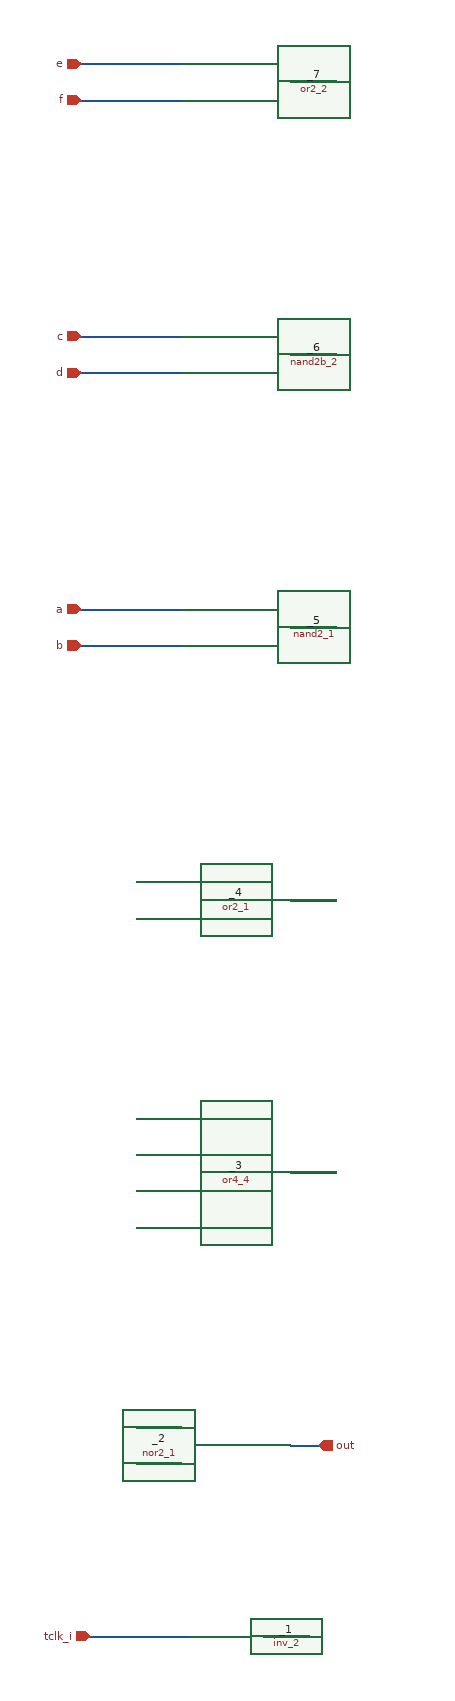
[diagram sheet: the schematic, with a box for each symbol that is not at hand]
v {xschem version=3.4.8RC file_version=1.3}
G {}
K {}
V {}
S {}
F {}
E {}
N 70 2800 180 2800 {lab=tclk_i}
N 60 1670 170 1670 {lab=a}
N 60 1710 170 1710 {lab=b}
N 60 1370 170 1370 {lab=c}
N 60 1410 170 1410 {lab=d}
N 60 1070 170 1070 {lab=e}
N 60 1110 170 1110 {lab=f}
N 290 1090 340 1090 {lab=#net1}
N 120 2310 170 2310 {lab=#net2}
N 120 2010 170 2010 {lab=#net3}
N 290 2290 340 2290 {lab=#net4}
N 120 2570 170 2570 {lab=#net5}
N 290 1690 340 1690 {lab=#net6}
N 120 2230 170 2230 {lab=#net7}
N 290 1990 340 1990 {lab=#net8}
N 120 2610 170 2610 {lab=#net9}
N 290 1390 340 1390 {lab=#net10}
N 120 2270 170 2270 {lab=#net11}
N 120 2350 170 2350 {lab=#net12}
N 260 2800 310 2800 {lab=#net13}
N 120 1970 170 1970 {lab=#net14}
N 290 2590 320 2590 {lab=out}
C {sky130_stdcells/inv_2.sym} 220 2800 0 0 {name=_1 VGND=VGND VNB=VNB VPB=VPB VPWR=VPWR prefix=sky130_fd_sc_hd__}
C {ipin.sym} 70 2800 0 0 {name=in_tclk_i_156 lab=tclk_i}
C {sky130_stdcells/nor2_1.sym} 230 2590 0 0 {name=_2 VGND=VGND VNB=VNB VPB=VPB VPWR=VPWR prefix=sky130_fd_sc_hd__}
C {sky130_stdcells/or4_4.sym} 230 2290 0 0 {name=_3 VGND=VGND VNB=VNB VPB=VPB VPWR=VPWR prefix=sky130_fd_sc_hd__}
C {sky130_stdcells/or2_1.sym} 230 1990 0 0 {name=_4 VGND=VGND VNB=VNB VPB=VPB VPWR=VPWR prefix=sky130_fd_sc_hd__}
C {sky130_stdcells/nand2_1.sym} 230 1690 0 0 {name=_5 VGND=VGND VNB=VNB VPB=VPB VPWR=VPWR prefix=sky130_fd_sc_hd__}
C {sky130_stdcells/nand2b_2.sym} 230 1390 0 0 {name=_6 VGND=VGND VNB=VNB VPB=VPB VPWR=VPWR prefix=sky130_fd_sc_hd__}
C {sky130_stdcells/or2_2.sym} 230 1090 0 0 {name=_7 VGND=VGND VNB=VNB VPB=VPB VPWR=VPWR prefix=sky130_fd_sc_hd__}
C {ipin.sym} 60 1670 0 0 {name=a lab=a}
C {ipin.sym} 60 1710 0 0 {name=b lab=b}
C {ipin.sym} 60 1370 0 0 {name=c lab=c}
C {ipin.sym} 60 1410 0 0 {name=d lab=d}
C {ipin.sym} 60 1070 0 0 {name=e lab=e}
C {ipin.sym} 60 1110 0 0 {name=f lab=f}
C {opin.sym} 320 2590 0 0 {name=out lab=out}
